# Copyright 2020 The SkyWater PDK Authors
#
# Licensed under the Apache License, Version 2.0 (the "License");
# you may not use this file except in compliance with the License.
# You may obtain a copy of the License at
#
#     https://www.apache.org/licenses/LICENSE-2.0
#
# Unless required by applicable law or agreed to in writing, software
# distributed under the License is distributed on an "AS IS" BASIS,
# WITHOUT WARRANTIES OR CONDITIONS OF ANY KIND, either express or implied.
# See the License for the specific language governing permissions and
# limitations under the License.
#
# SPDX-License-Identifier: Apache-2.0

VERSION 5.7 ;
  NOWIREEXTENSIONATPIN ON ;
  DIVIDERCHAR "/" ;
  BUSBITCHARS "[]" ;
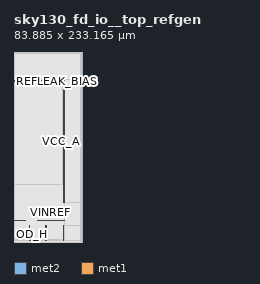
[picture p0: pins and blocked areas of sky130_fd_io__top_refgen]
MACRO sky130_fd_io__top_refgen
  CLASS BLOCK ;
  FOREIGN sky130_fd_io__top_refgen ;
  ORIGIN  0.045000  1.965000 ;
  SIZE  83.88500 BY  233.1650 ;
  PIN HLD_H_N
    PORT
      LAYER met2 ;
        RECT 20.555000 0.000000 20.815000 10.230000 ;
    END
  END HLD_H_N
  PIN IBUF_SEL
    PORT
      LAYER met2 ;
        RECT 38.250000 0.000000 38.510000 17.950000 ;
    END
  END IBUF_SEL
  PIN OD_H
    PORT
      LAYER met2 ;
        RECT 19.180000 0.000000 19.440000 3.790000 ;
    END
  END OD_H
  PIN REFLEAK_BIAS
    PORT
      LAYER met1 ;
        RECT 0.000000 194.905000 7.485000 195.135000 ;
    END
    PORT
      LAYER met1 ;
        RECT 45.105000 194.905000 62.050000 195.135000 ;
    END
  END REFLEAK_BIAS
  PIN VCC_A
    PORT
      LAYER met2 ;
        RECT 1.725000 194.400000 2.390000 196.860000 ;
    END
    PORT
      LAYER met2 ;
        RECT 42.385000 195.555000 44.335000 196.860000 ;
    END
    PORT
      LAYER met2 ;
        RECT 60.190000 46.675000 61.745000 196.860000 ;
    END
    PORT
      LAYER met2 ;
        RECT 8.965000 195.555000 10.110000 196.860000 ;
    END
  END VCC_A
  PIN VINREF
    PORT
      LAYER met1 ;
        RECT 0.080000 23.915000 14.480000 24.175000 ;
    END
    PORT
      LAYER met1 ;
        RECT 28.250000 23.915000 61.970000 24.175000 ;
    END
  END VINREF
  PIN VOHREF
    PORT
      LAYER met2 ;
        RECT 24.980000 195.190000 25.240000 196.760000 ;
    END
    PORT
      LAYER met2 ;
        RECT 30.705000 0.000000 30.965000 10.100000 ;
    END
  END VOHREF
  PIN VOUTREF
    PORT
      LAYER met1 ;
        RECT 0.000000 196.100000 40.510000 196.360000 ;
    END
    PORT
      LAYER met1 ;
        RECT 42.050000 196.100000 62.050000 196.360000 ;
    END
  END VOUTREF
  PIN VREF_SEL
    PORT
      LAYER met2 ;
        RECT 39.415000 0.000000 39.675000 17.950000 ;
    END
  END VREF_SEL
  PIN VREG_EN
    PORT
      LAYER met2 ;
        RECT 60.400000 0.000000 60.660000 17.825000 ;
    END
  END VREG_EN
  PIN VTRIP_SEL
    PORT
      LAYER met2 ;
        RECT 18.400000 0.000000 18.660000 17.950000 ;
    END
  END VTRIP_SEL
  OBS
    LAYER li1 ;
      RECT 0.335000 -1.940000 83.240000 230.600000 ;
    LAYER met1 ;
      RECT  0.310000  -1.965000 83.240000  23.635000 ;
      RECT  0.310000  24.455000 83.240000 194.625000 ;
      RECT  0.310000 195.415000 83.240000 195.820000 ;
      RECT  0.310000 196.640000 83.240000 230.600000 ;
      RECT  7.765000 194.625000 44.825000 195.415000 ;
      RECT 14.760000  23.635000 27.970000  24.455000 ;
      RECT 40.790000 195.820000 41.770000 196.640000 ;
      RECT 62.250000  23.635000 83.240000  24.455000 ;
      RECT 62.330000 194.625000 83.240000 195.415000 ;
      RECT 62.330000 195.820000 83.240000 196.640000 ;
    LAYER met2 ;
      RECT  0.295000  -1.965000 82.005000  -0.280000 ;
      RECT  0.295000  -0.280000 18.120000  18.230000 ;
      RECT  0.295000  18.230000 82.005000  46.395000 ;
      RECT  0.295000  46.395000 59.910000 194.120000 ;
      RECT  0.295000 194.120000  1.445000 197.140000 ;
      RECT  0.295000 197.140000 82.005000 229.365000 ;
      RECT  2.670000 194.120000 59.910000 194.910000 ;
      RECT  2.670000 194.910000 24.700000 195.275000 ;
      RECT  2.670000 195.275000  8.685000 197.140000 ;
      RECT 10.390000 195.275000 24.700000 197.040000 ;
      RECT 10.390000 197.040000 42.105000 197.140000 ;
      RECT 18.940000   4.070000 20.275000  10.510000 ;
      RECT 18.940000  10.510000 37.970000  18.230000 ;
      RECT 19.720000  -0.280000 20.275000   4.070000 ;
      RECT 21.095000  -0.280000 30.425000  10.380000 ;
      RECT 21.095000  10.380000 37.970000  10.510000 ;
      RECT 25.520000 194.910000 59.910000 195.275000 ;
      RECT 25.520000 195.275000 42.105000 197.040000 ;
      RECT 31.245000  -0.280000 37.970000  10.380000 ;
      RECT 38.790000  -0.280000 39.135000  18.230000 ;
      RECT 39.955000  -0.280000 60.120000  18.105000 ;
      RECT 39.955000  18.105000 82.005000  18.230000 ;
      RECT 44.615000 195.275000 59.910000 197.140000 ;
      RECT 60.940000  -0.280000 82.005000  18.105000 ;
      RECT 62.025000  46.395000 82.005000 197.140000 ;
    LAYER met3 ;
      RECT 0.000000 1.250000 62.100000 67.995000 ;
  END
END sky130_fd_io__top_refgen
END LIBRARY
